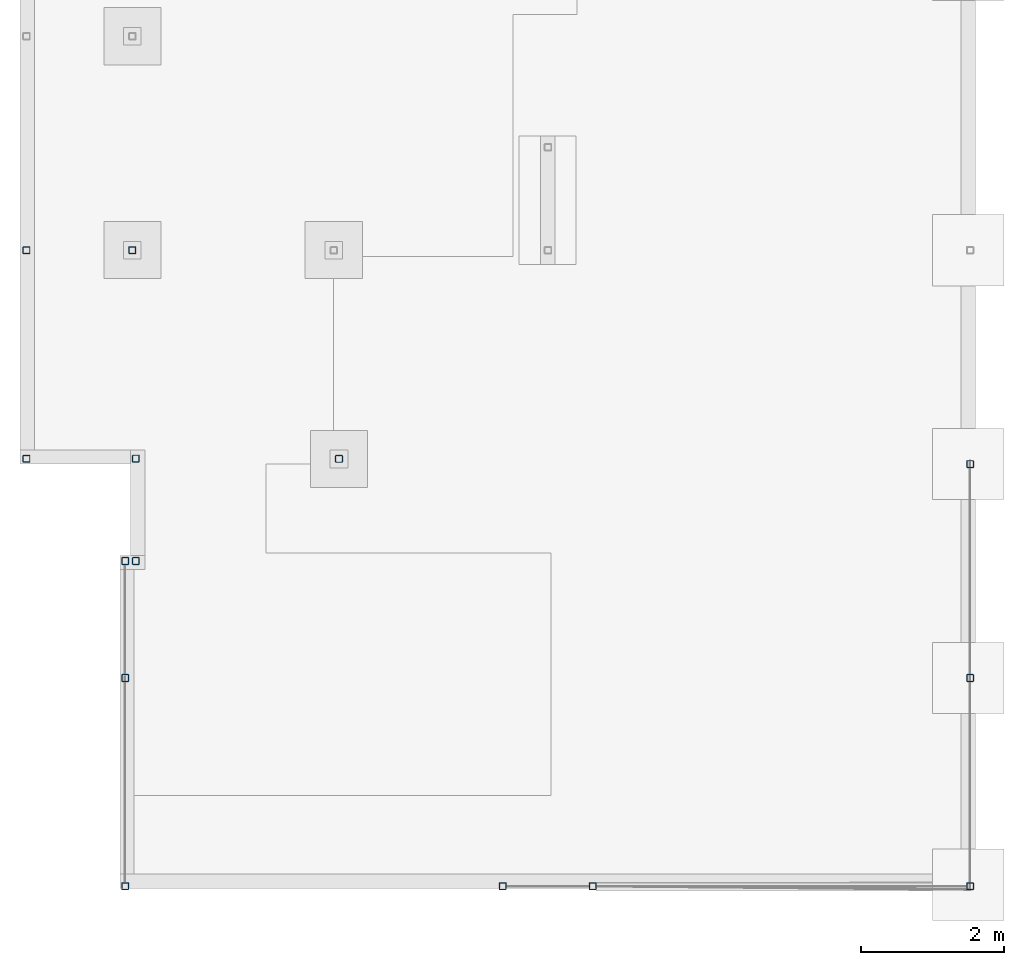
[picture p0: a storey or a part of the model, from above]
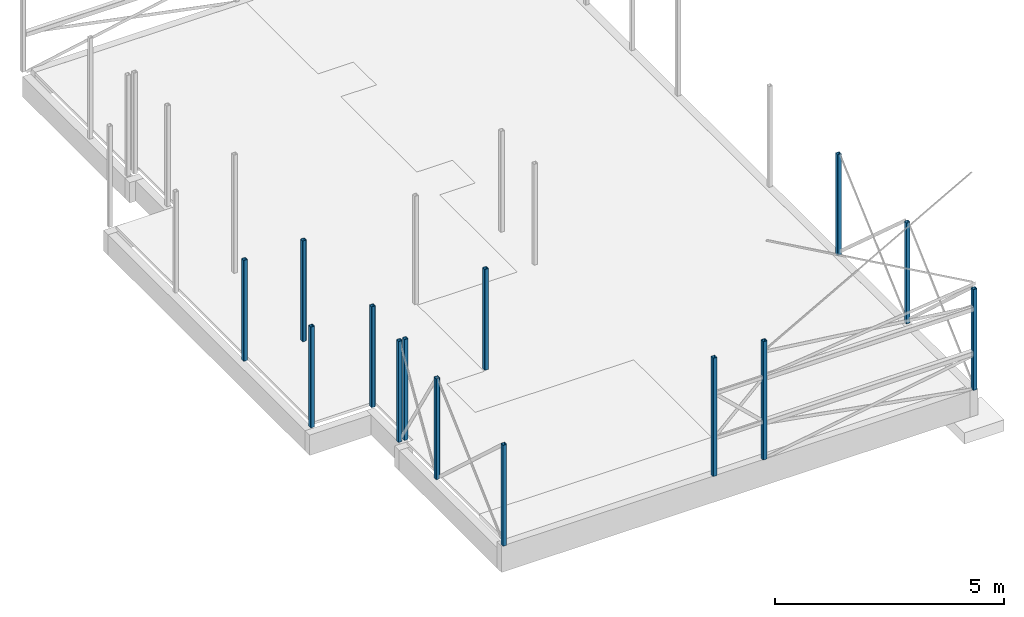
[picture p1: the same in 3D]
Properties of the parts of a building model (IFC2X3)

# File
Description: ViewDefinition [CoordinationView_V2.0]
File name: 17-036
Time: 2018-02-02T19:05:55
Written by: The EXPRESS Data Manager Version 5.02.0100.07 : 28 Aug 2013
Made in: 20170927_1515(x64) - Exporter 18.2.0.51 - Alternate UI 18.2.0.51
Comment: STEP Physical File produced by: The EXPRESS Data Manager Version 5.02.0100.07 : 28 Aug 2013 * Module: EDMstepFileFactory/EDMstandAlone * Creation date: Fri Feb 02 19:05:55 2018 * Host: DESKTOP-K52CJEA * Database: C:\Users\tt\AppData\Local\Temp\{F509D24D-F691-49AB-BC9F-CBD7F8E59786}\ifc * Database version: 5507 * Database creation date: Fri Feb 02 19:05:51 2018 * Schema: IFC2X3 * Model: DataRepository.ifc * Model creation date: Fri Feb 02 19:05:51 2018 * Header model: DataRepository.ifc_HeaderModel * Header model creation date: Fri Feb 02 19:05:51 2018 * EDMuser: sdai-user * EDMgroup: sdai-group * License ID and type: 5605 : Permanent license. Expiry date: * EDMstepFileFactory options: 020000

# IfcProject, 17-036
LongName: BRANNSTASJON GJESDAL

# IfcSite, Default
RefLatitude: 59, 54, 57, 599999; RefLongitude: 10, 44, 59, 999999; RefElevation: 101000 mm

# IfcBuildingStorey (3)
Procon - Type: Nivå 8mm Project
Name | LongName | Elevation (mm)
01 | 01 | 8.92956e-10
02 | 02 | 3150
03 | 03 | 6025

# IfcBeam: Bjelke HUP:HUP 100x100x5 (3)
In: 03
Type - PredefinedType: BEAM
Pset_VDC - Fase: Existing
Procon - Type: HUP 100x100x5; B: 100 mm; h: 100 mm; b: 100 mm
Name (Bjelke HUP:HUP 100x100x5:...)
907845
912680
912808

# IfcBeam: Bjelke HUP:HUP 100x50x5 (2)
In: 01
Type - PredefinedType: BEAM
Material: S355
Pset_VDC - Fase: Existing
Procon - Type: HUP 100x50x5; B: 50 mm; h: 100 mm; b: 50 mm; Materiale: S355
Name (Bjelke HUP:HUP 100x50x5:...)
834604
834900

# IfcBeam: Bjelke HUP:HUP 120x120x5 (18)
Type - PredefinedType: BEAM
Material: S355
Pset_VDC - Fase: Existing
Procon - Type: HUP 120x120x5; B: 120 mm; h: 120 mm; b: 120 mm; Materiale: S355
Name (Bjelke HUP:HUP 120x120x5:...) | In
835029 | 01
835167 | 01
842518 | 03
848209 | 01
853000 | 03
856602 | 03
857134 | 03
907847 | 03
909423 | 03
912682 | 03
912734 | 03
912810 | 03
912862 | 03
993462 | 03
995219 | 03
995261 | 03
995296 | 03
995330 | 03

# IfcBeam: Bjelke IPE:IPE 200 (9)
Type - PredefinedType: BEAM
Material: Stål - S355
Pset_VDC - Fase: Existing
Procon - Type: IPE 200; s: 5.6 mm; B: 100 mm; h: 200 mm; b: 100 mm
Name (Bjelke IPE:IPE 200:...) | In | Materiale
827796 | 02 | B500C
827884 | 02 | S355
828501 | 02 | B500C
828737 | 02 | S355
849826 | 03 | B500C
850250 | 03 | B500C
989715 | 02 | B500C
989818 | 02 | B500C
989849 | 02 | B500C

# IfcBeam: Bjelke Stålplate:40x5 mm (6)
Type - PredefinedType: BEAM
Material: Structural Framing Fireproofing
Pset_VDC - Fase: Existing
Procon - Type: 40x5 mm; B: 5 mm; h: 40 mm; b: 5 mm; Materiale: B500C
Name (Bjelke Stålplate:40x5 mm:...) | In
840561 | 01
840626 | 01
860526 | 02
860853 | 02
861374 | 02
861407 | 02

# IfcBeam: Bjelke Stålplate:VINDKRYSS (24)
Type - PredefinedType: BEAM
Material: Structural Framing Fireproofing
Pset_VDC - Fase: Existing
Procon - Type: VINDKRYSS; B: 8 mm; h: 80 mm; b: 8 mm; Materiale: S355
Name (Bjelke Stålplate:VINDKRYSS:...) | In
837247 | 01
837501 | 01
837691 | 01
837693 | 01
839909 | 01
840269 | 01
848571 | 01
848618 | 01
848719 | 01
848820 | 01
849208 | 01
849243 | 01
862490 | 01
862522 | 01
862570 | 01
862615 | 01
863401 | 02
863636 | 02
863878 | 02
864350 | 02
996140 | 01
996142 | 01
996144 | 01
1005922 | 01

# IfcColumn: HUP 100x100x6.3 (58)
Type - ElementType: HUP 100x100x6.3; PredefinedType: COLUMN; Material: S355
Pset_VDC - Fase: Existing
Procon - Type: HUP 100x100x6.3; B: 100 mm; h: 100 mm; b: 100 mm; Materiale: S355
Name (Søyle HUP:HUP 100x100x6.3:...) | In
817394 | 01
817816 | 01
817874 | 01
817895 | 01
817935 | 01
818292 | 01
818311 | 01
818334 | 01
818351 | 01
818370 | 01
818389 | 01
818408 | 01
818427 | 01
818446 | 01
818465 | 01
818529 | 01
818574 | 01
818593 | 01
818724 | 01
818743 | 01
822377 | 02
822912 | 02
822927 | 02
822942 | 02
822972 | 02
822987 | 02
823002 | 02
823017 | 02
823032 | 02
823098 | 02
823113 | 02
823177 | 02
823192 | 02
823207 | 02
836697 | 01
842414 | 02
989898 | 01
989908 | 01
989921 | 01
989933 | 01
989943 | 01
989954 | 01
989965 | 01
989978 | 01
989987 | 01
989997 | 01
990053 | 01
992850 | 02
992885 | 02
992922 | 02
992947 | 02
992982 | 02
993013 | 02
993015 | 02
993061 | 02
993063 | 02
993112 | 02
993143 | 02

# IfcElementAssembly: Gitterdrager:Standard (3)
In: 03
PredefinedType: TRUSS
Pset_VDC - Fase: Existing
Procon - Type: Standard
Name (Gitterdrager:Standard:...)
907843
912679
912807

# IfcMember: 60x60x5 (69)
In: 03
Type - ElementType: 60x60x5; PredefinedType: BRACE
Pset_VDC - Fase: Existing
Procon - Type: 60x60x5; B: 60 mm; h: 60 mm; b: 60 mm
Name (Bjelke HUP:60x60x5:...)
908123
908125
908127
908129
908131
908133
908135
908137
908139
908141
908143
908145
908147
908149
908151
908153
908155
908157
908159
908161
908163
908165
908167
912688
912690
912692
912694
912696
912698
912700
912702
912704
912706
912708
912710
912712
912714
912716
912718
912720
912722
912724
912726
912728
912730
912732
912816
912818
912820
912822
912824
912826
912828
912830
912832
912834
912836
912838
912840
912842
912844
912846
912848
912850
912852
912854
912856
912858
912860

# IfcOpeningElement: Opening (2)
In: 01
Pset_VDC - Fase: Existing
Procon - Type: OPPKANT B=200, (140); OD Innvendig: Rebar Cover Settings: 25 mm; OD Utvendig: Rebar Cover Settings: 25 mm; OD Generelt: Rebar Cover Settings: 25 mm; Materiale: Betong Plasstøpt - B35
Name (Basic Wall:OPPKANT B=200, (140):...)
805795
810791

# IfcSlab: Floor:BETONG 70, Floor:BETONG 70:1011686
In: 01
PredefinedType: FLOOR; Material: Betong Plasstøpt - B30 70 mm
Pset_VDC - Fase: Existing
Procon - Type: BETONG 70; OD Topp: Rebar Cover Settings: 25 mm; OD Bunn: Rebar Cover Settings: 25 mm; OD Generelt: Rebar Cover Settings: 25 mm; Bruk: Betongdekke; Materiale: Betong Plasstøpt - B30

# IfcSlab: Floor:BETONG 70+50, Floor:BETONG 70+50:816883
In: 01
PredefinedType: FLOOR; Material: Betong Plasstøpt - B30 70 mm, EPS 50 mm
Pset_VDC - Fase: Existing
Procon - Type: BETONG 70+50; OD Topp: Rebar Cover Settings: 25 mm; OD Bunn: Rebar Cover Settings: 25 mm; OD Generelt: Rebar Cover Settings: 25 mm; Bruk: Betongdekke; Materiale: Betong Plasstøpt - B30

# IfcSlab: Floor:HD-265 (2)
In: 02
PredefinedType: FLOOR; Material: HD1200mm 265 mm
Pset_VDC - Fase: Existing
Procon - Type: HD-265; OD Topp: Rebar Cover Settings: 25 mm; OD Bunn: Rebar Cover Settings: 25 mm; OD Generelt: Rebar Cover Settings: 25 mm; Bruk: Hulldekker; Materiale: HD1200mm
Name (Floor:HD-265:...)
828784
987904

# IfcSlab: Fundament med knast:800x800x300 (4)
In: 01
PredefinedType: FLOOR; Material: Betong Plasstøpt - B35
Pset_VDC - Fase: Existing
Procon - Type: 800x800x300; OD Topp: Rebar Cover Settings: 25 mm; OD Bunn: Rebar Cover Settings: 25 mm; OD Generelt: Rebar Cover Settings: 25 mm; Bruk: Punktfundament; Materiale: Betong Plasstøpt - B35
Name (Fundament med knast:800x800x300:...)
811937
812203
812445
945172

# IfcSlab: Punktfundament:1800x800x300, Punktfundament:1800x800x300:813598
In: 01
PredefinedType: FLOOR; Material: Betong Plasstøpt - B35
Pset_VDC - Fase: Existing
Procon - Type: 1800x800x300; OD Topp: Rebar Cover Settings: 25 mm; OD Bunn: Rebar Cover Settings: 25 mm; OD Generelt: Rebar Cover Settings: 25 mm; Bruk: Punktfundament; Materiale: Betong Plasstøpt - B35

# IfcSlab: Punktfundament:Betong 1000x1000x300mm (9)
In: 01
PredefinedType: FLOOR; Material: Betong Plasstøpt - B35
Pset_VDC - Fase: Existing
Procon - Type: Betong 1000x1000x300mm; OD Topp: Rebar Cover Settings: 25 mm; OD Bunn: Rebar Cover Settings: 25 mm; OD Generelt: Rebar Cover Settings: 25 mm; Bruk: Punktfundament; Materiale: Betong Plasstøpt - B35
Name (Punktfundament:Betong 1000x1000x300mm:...)
807751
807992
808117
808202
808359
808446
808525
808620
809325

# IfcWallStandardCase: Basic Wall:BETONG 200, Basic Wall:BETONG 200:815344
In: 01
Type - PredefinedType: STANDARD; Material: Betong Plasstøpt - B35 200 mm
Pset_VDC - Fase: Existing
Procon - Type: BETONG 200; OD Innvendig: Rebar Cover Settings: 25 mm; OD Utvendig: Rebar Cover Settings: 25 mm; OD Generelt: Rebar Cover Settings: 25 mm; Materiale: Betong Plasstøpt - B35

# IfcWallStandardCase: Basic Wall:OPPKANT B=200, (140) (12)
In: 01
Type - PredefinedType: STANDARD; Material: Betong Plasstøpt - B35 200 mm
Pset_VDC - Fase: Existing
Procon - Type: OPPKANT B=200, (140); OD Innvendig: Rebar Cover Settings: 25 mm; OD Utvendig: Rebar Cover Settings: 25 mm; OD Generelt: Rebar Cover Settings: 25 mm; Materiale: Betong Plasstøpt - B35
Name (Basic Wall:OPPKANT B=200, (140):...)
804726
805097
805292
805795
806116
807057
807259
810111
810346
810445
810661
810791
